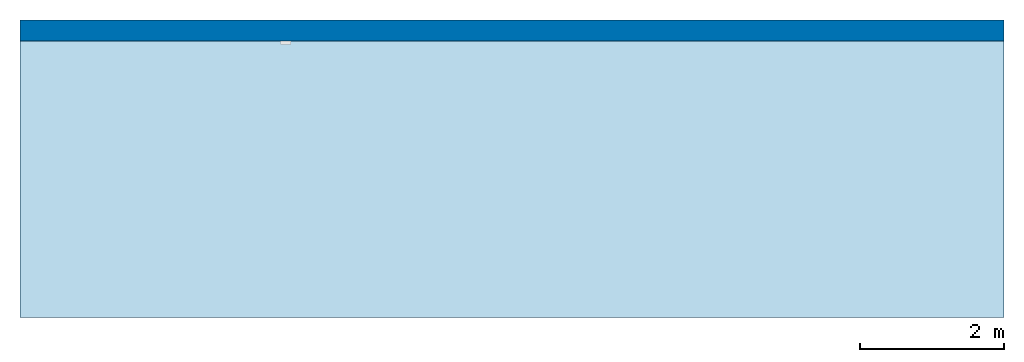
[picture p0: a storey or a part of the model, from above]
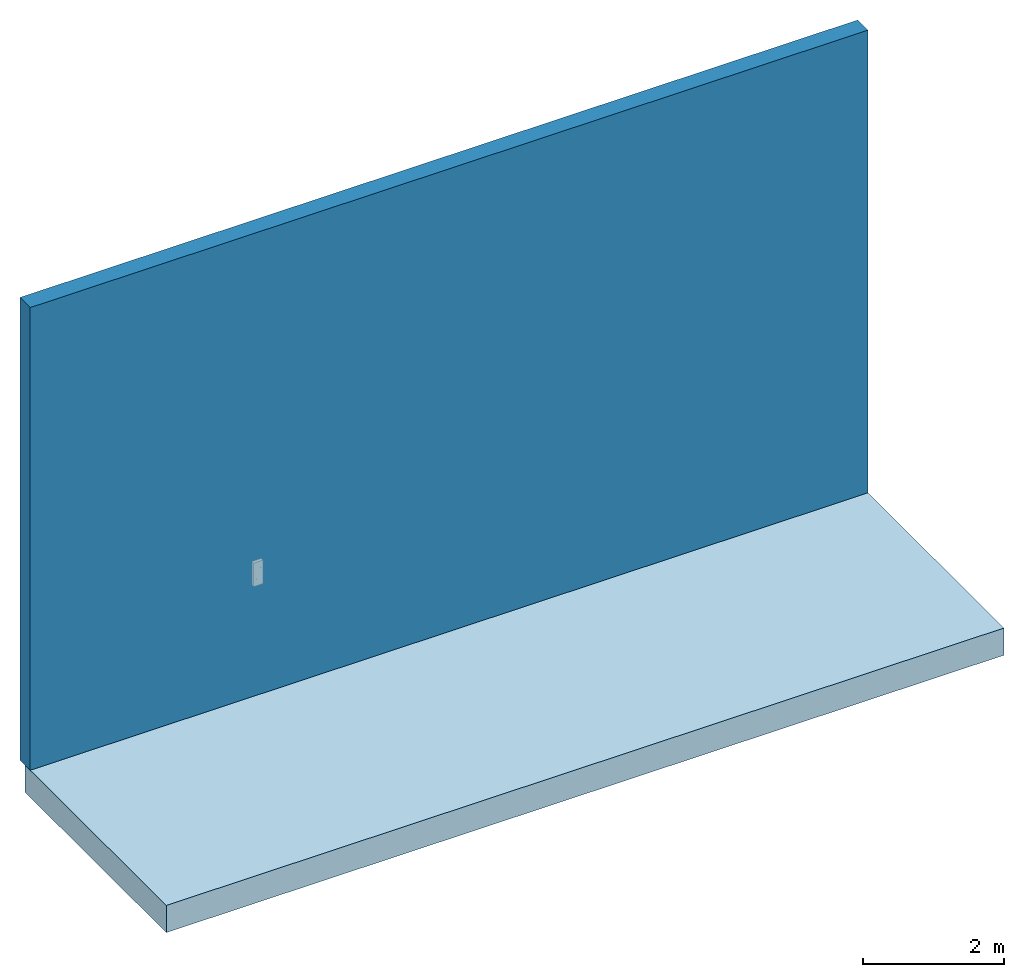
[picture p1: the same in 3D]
Properties of the parts of a building model (IFC2X3)

# File
Description: ViewDefinition [CoordinationView_V2.0]
File name: Project Number
Time: 2021-07-09T22:50:16
Written by: The EXPRESS Data Manager Version 5.02.0100.07 : 28 Aug 2013
Made in: 20160225_1515(x64) - Exporter 17.0.416.0 - Alternate UI 17.12.14.0
Comment: STEP Physical File produced by: The EXPRESS Data Manager Version 5.02.0100.07 : 28 Aug 2013 * Module: EDMstepFileFactory/EDMstandAlone * Creation date: Fri Jul 09 22:50:16 2021 * Host: JRLAP21DELL * Database: C:\Users\JAMESR~1\AppData\Local\Temp\{B6AA690A-BA1E-454C-9D73-A224FCF8660D}\ifc * Database version: 5507 * Database creation date: Fri Jul 09 22:50:14 2021 * Schema: IFC2X3 * Model: DataRepository.ifc * Model creation date: Fri Jul 09 22:50:15 2021 * Header model: DataRepository.ifc_HeaderModel * Header model creation date: Fri Jul 09 22:50:15 2021 * EDMuser: sdai-user * EDMgroup: sdai-group * License ID and type: 5605 : Permanent license. Expiry date: * EDMstepFileFactory options: 020000

# IfcProject, Project Number
LongName: Project Name; Phase: Project Status

# IfcSite, Default
RefLatitude: 51, 30, 23, 112487; RefLongitude: 0, -7, -37, -956022; RefElevation: 0 mm

# IfcBuilding
Pset_BuildingCommon - NumberOfStoreys: 1

# IfcBuildingStorey, Level 0
LongName: Level 0; Elevation: 0 mm

# IfcBuildingElementProxy: XVP S, Electrical Fixture_CAME_XVP S:XVP S:376157
In: Level 0
Type - Material: Bright White, Black Screen
Pset_BuildingElementProxyCommon - Reference: XVP S
Pset_ManufacturerTypeInformation - ModelReference: XVP S; Manufacturer: CAME S.p.A.

# IfcSlab: Floor:Floor-Grnd-Susp_65Scr-80Ins-100Blk-75PC, Floor:Floor-Grnd-Susp_65Scr-80Ins-100Blk-75PC:303813
In: Level 0
PredefinedType: FLOOR; Material: Concrete, Sand/Cement Screed 65 mm, Rigid insulation 80 mm, Air 150 mm, Concrete Masonry, Floor Block 100 mm, Concrete, Precast 75 mm
Pset_SlabCommon - Reference: Floor-Grnd-Susp_65Scr-80Ins-100Blk-75PC; IsExternal: no; LoadBearing: yes; ThermalTransmittance: 0.117438 kg/K/s3; PitchAngle: 0 deg

# IfcWallStandardCase: Basic Wall:Wall-Ext_102Bwk-75Ins-100LBlk-12P, Basic Wall:Wall-Ext_102Bwk-75Ins-100LBlk-12P:303877
In: Level 0
Type - PredefinedType: STANDARD; Material: Brick, Common 102.5 mm, Fiberglass Batt 75 mm, Concrete Masonry Units _Low Density 100 mm, Plaster 12.5 mm
Pset_WallCommon - Reference: Wall-Ext_102Bwk-75Ins-100LBlk-12P; LoadBearing: no; ExtendToStructure: no; IsExternal: yes; ThermalTransmittance: 0.235926 kg/K/s3
